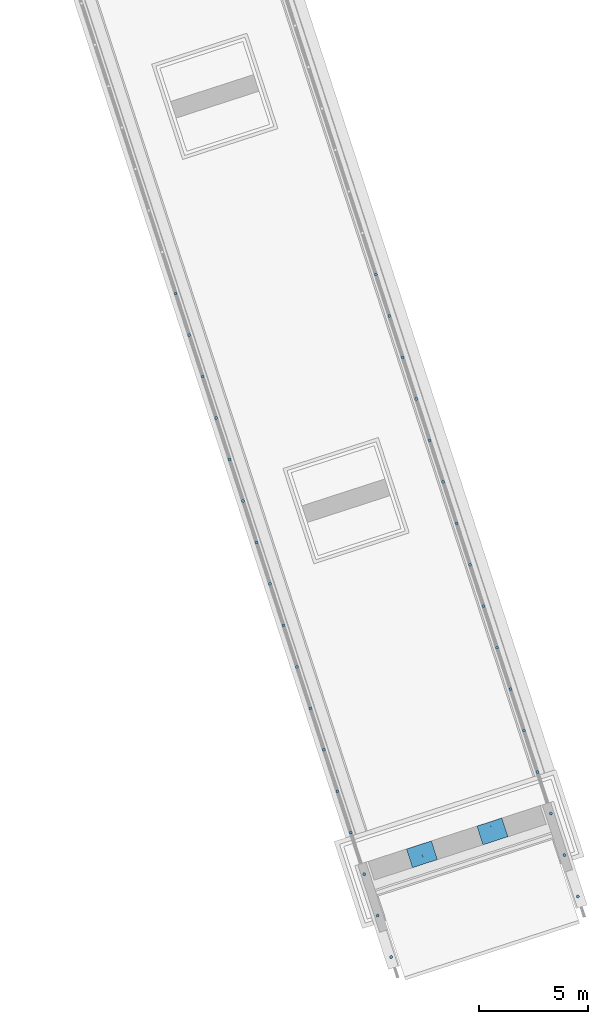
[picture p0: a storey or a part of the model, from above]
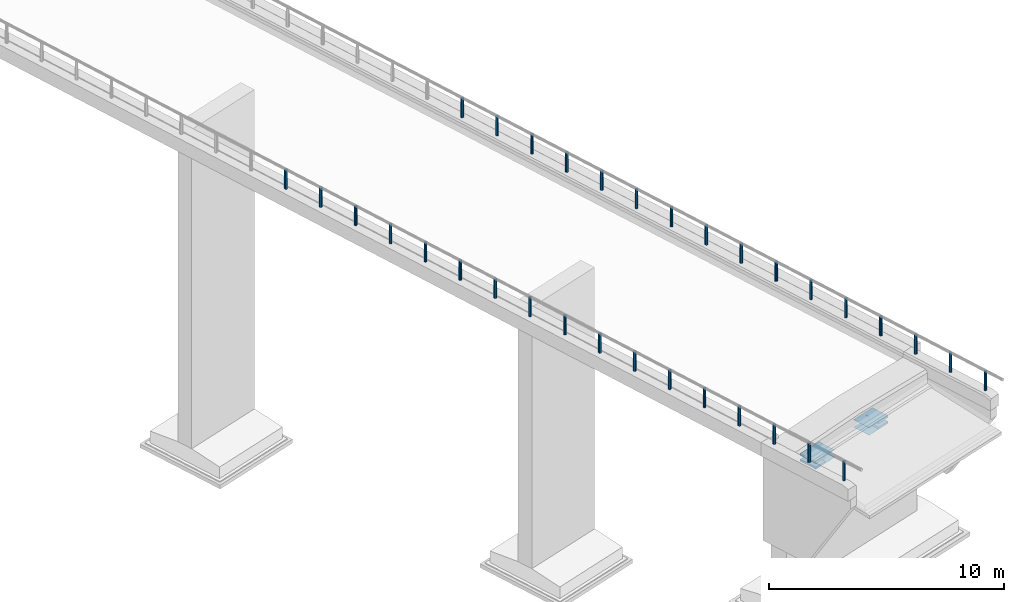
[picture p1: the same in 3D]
Properties of the parts of a building model (IFC4X3_ADD2)

# File
Description: ViewDefinition [ReferenceView]
File name: 03_Bridge_BEST_IFC4x3.ifc
Time: 2026-09-28T12:00:00
Author: Marcin Pszczolka
Organization: BIM Corner
Written by: IfcOpenShell 0.8.5
Made in: BIM Corner - IFC Bridge Masterclass generator 1.0
Authorization: Marcin Pszczolka, BIM Corner

# IfcProject: Bridge design project, BR-01
LongName: BR-01 demo bridge - 4D exercise; Phase: Detailed design

# IfcSite, Site BR-01
Description: Georeferenced: EUREF89 NTM10 (EPSG:5110), heights NN2000. Project base point E 145700 / N 6566100 / H 0.; LongName: Bridge IFC Masterclass site

# IfcBeam (10)
Name | In | Description | PredefinedType
End diaphragm A1 | Deck | End diaphragm - Abutment A1 (north) | DIAPHRAGM
End diaphragm A2 | Deck | End diaphragm - Abutment A2 (south) | DIAPHRAGM
Edge beam left outer | Deck | Edge beam - superstructure | EDGEBEAM
Edge beam right inner | Deck | Edge beam - superstructure | EDGEBEAM
Wing wall edge beam A1 left | A1 | Wing wall edge beam - Abutment A1 (north) | EDGEBEAM
Wing wall edge beam A1 right | A1 | Wing wall edge beam - Abutment A1 (north) | EDGEBEAM
Wing wall edge beam A2 left | A2 | Wing wall edge beam - Abutment A2 (south) | EDGEBEAM
Wing wall edge beam A2 right | A2 | Wing wall edge beam - Abutment A2 (south) | EDGEBEAM
Edge beam left inner | Deck | Edge beam - superstructure | EDGEBEAM
Edge beam right outer | Deck | Edge beam - superstructure | EDGEBEAM

# IfcBearing (4)
PredefinedType: ELASTOMERIC
Name | In | Description
Bridge bearing A1 left | A1 | Bridge bearing - Abutment A1 (north)
Bridge bearing A1 right | A1 | Bridge bearing - Abutment A1 (north)
Bridge bearing A2 left | A2 | Bridge bearing - Abutment A2 (south)
Bridge bearing A2 right | A2 | Bridge bearing - Abutment A2 (south)

# IfcBridge: SLAB_BRIDGE, BR-01
Description: Continuous cast-in-place slab bridge, 5 spans, L = 87.1 m; LongName: Demo slab bridge over a valley; PredefinedType: USERDEFINED; Constraint: Design working life 100 years

# IfcBridgePart (9)
Name | LongName | UsageType | PredefinedType
Substructure | Substructure (piers and abutments) | VERTICAL | SUBSTRUCTURE
Superstructure | Superstructure (deck) | LONGITUDINAL | SUPERSTRUCTURE
A1 | Abutment A1 (north) | VERTICAL | ABUTMENT
P1 | Pier P1 | VERTICAL | PIER
P2 | Pier P2 | VERTICAL | PIER
P3 | Pier P3 | VERTICAL | PIER
P4 | Pier P4 | VERTICAL | PIER
A2 | Abutment A2 (south) | VERTICAL | ABUTMENT
Deck | Bridge deck | LONGITUDINAL | DECK

# IfcColumn (4)
PredefinedType: PIERSTEM
Name | In | Description
Pier wall P1 | P1 | Pier wall - Pier P1
Pier wall P2 | P2 | Pier wall - Pier P2
Pier wall P3 | P3 | Pier wall - Pier P3
Pier wall P4 | P4 | Pier wall - Pier P4

# IfcEarthworksFill: CRUSHEDSTONEBED (8)
PredefinedType: USERDEFINED
Name | In | Description
Approach slab stone bed A1 | A1 | Approach slab stone bed - Abutment A1 (north)
Approach slab stone bed A2 | A2 | Approach slab stone bed - Abutment A2 (south)
Crushed stone bed A1 | A1 | Crushed stone bed - Abutment A1 (north)
Crushed stone bed A2 | A2 | Crushed stone bed - Abutment A2 (south)
Crushed stone bed P1 | P1 | Crushed stone bed - Pier P1
Crushed stone bed P2 | P2 | Crushed stone bed - Pier P2
Crushed stone bed P3 | P3 | Crushed stone bed - Pier P3
Crushed stone bed P4 | P4 | Crushed stone bed - Pier P4

# IfcFooting (6)
Name | In | Description | PredefinedType
Abutment strip footing A1 | A1 | Abutment strip footing - Abutment A1 (north) | STRIP_FOOTING
Abutment strip footing A2 | A2 | Abutment strip footing - Abutment A2 (south) | STRIP_FOOTING
Pier pad footing P1 | P1 | Pier pad footing - Pier P1 | PAD_FOOTING
Pier pad footing P2 | P2 | Pier pad footing - Pier P2 | PAD_FOOTING
Pier pad footing P3 | P3 | Pier pad footing - Pier P3 | PAD_FOOTING
Pier pad footing P4 | P4 | Pier pad footing - Pier P4 | PAD_FOOTING

# IfcMember: Railing post D140 (98)
In: Deck
Type - Description: Railing post; PredefinedType: POST
Description: Railing post - superstructure
Name
Railing post left 01
Railing post left 02
Railing post left 03
Railing post left 04
Railing post left 05
Railing post left 06
Railing post left 07
Railing post left 08
Railing post left 09
Railing post left 10
Railing post left 11
Railing post left 12
Railing post left 13
Railing post left 14
Railing post left 15
Railing post left 16
Railing post left 17
Railing post left 18
Railing post left 19
Railing post left 20
Railing post left 21
Railing post left 22
Railing post left 23
Railing post left 24
Railing post left 25
Railing post left 26
Railing post left 27
Railing post left 28
Railing post left 29
Railing post left 30
Railing post left 31
Railing post left 32
Railing post left 33
Railing post left 34
Railing post left 35
Railing post left 36
Railing post left 37
Railing post left 38
Railing post left 39
Railing post left 40
Railing post left 41
Railing post left 42
Railing post left 43
Railing post left 44
Railing post left 45
Railing post left 46
Railing post left 47
Railing post left 48
Railing post left 49
Railing post right 01
Railing post right 02
Railing post right 03
Railing post right 04
Railing post right 05
Railing post right 06
Railing post right 07
Railing post right 08
Railing post right 09
Railing post right 10
Railing post right 11
Railing post right 12
Railing post right 13
Railing post right 14
Railing post right 15
Railing post right 16
Railing post right 17
Railing post right 18
Railing post right 19
Railing post right 20
Railing post right 21
Railing post right 22
Railing post right 23
Railing post right 24
Railing post right 25
Railing post right 26
Railing post right 27
Railing post right 28
Railing post right 29
Railing post right 30
Railing post right 31
Railing post right 32
Railing post right 33
Railing post right 34
Railing post right 35
Railing post right 36
Railing post right 37
Railing post right 38
Railing post right 39
Railing post right 40
Railing post right 41
Railing post right 42
Railing post right 43
Railing post right 44
Railing post right 45
Railing post right 46
Railing post right 47
Railing post right 48
Railing post right 49

# IfcMember: TOPRAIL (2)
In: Deck
Description: Railing top rail - superstructure; PredefinedType: USERDEFINED
Name
Railing top rail left
Railing top rail right

# IfcProjectLibrary, BIM Corner bridge library
Description: Types and property set templates for bridge projects; Phase: Detailed design

# IfcRailing (2)
In: Deck
PredefinedType: GUARDRAIL
Name | Description
Bridge railing left | Bridge railing left - 49 posts
Bridge railing right | Bridge railing right - 49 posts

# IfcSlab (2)
PredefinedType: APPROACH_SLAB
Name | In | Description
Approach slab A1 | A1 | Approach slab - Abutment A1 (north)
Approach slab A2 | A2 | Approach slab - Abutment A2 (south)

# IfcSlab: BLINDING (8)
PredefinedType: USERDEFINED
Name | In | Description
Approach slab blinding A1 | A1 | Approach slab blinding - Abutment A1 (north)
Approach slab blinding A2 | A2 | Approach slab blinding - Abutment A2 (south)
Blinding concrete A1 | A1 | Blinding concrete - Abutment A1 (north)
Blinding concrete A2 | A2 | Blinding concrete - Abutment A2 (south)
Blinding concrete P1 | P1 | Blinding concrete - Pier P1
Blinding concrete P2 | P2 | Blinding concrete - Pier P2
Blinding concrete P3 | P3 | Blinding concrete - Pier P3
Blinding concrete P4 | P4 | Blinding concrete - Pier P4

# IfcSlab: BRIDGEDECK, Bridge deck slab
In: Deck
Description: Bridge deck slab - superstructure; PredefinedType: USERDEFINED

# IfcWall (2)
PredefinedType: RETAININGWALL
Name | In | Description
Abutment front wall A1 | A1 | Abutment front wall - Abutment A1 (north)
Abutment front wall A2 | A2 | Abutment front wall - Abutment A2 (south)

# IfcWall: WINGWALL (4)
PredefinedType: USERDEFINED
Name | In | Description
Wing wall A1 left | A1 | Wing wall - Abutment A1 (north)
Wing wall A1 right | A1 | Wing wall - Abutment A1 (north)
Wing wall A2 left | A2 | Wing wall - Abutment A2 (south)
Wing wall A2 right | A2 | Wing wall - Abutment A2 (south)
